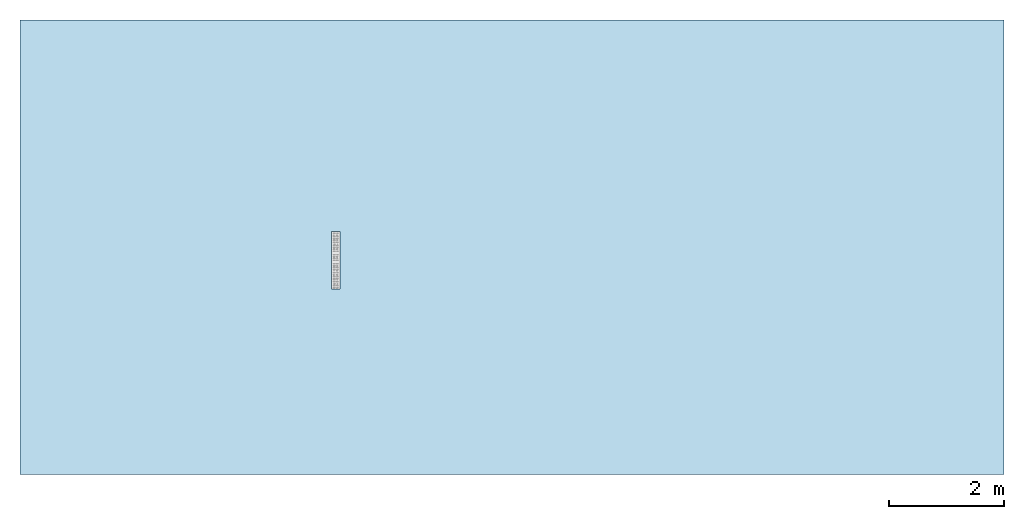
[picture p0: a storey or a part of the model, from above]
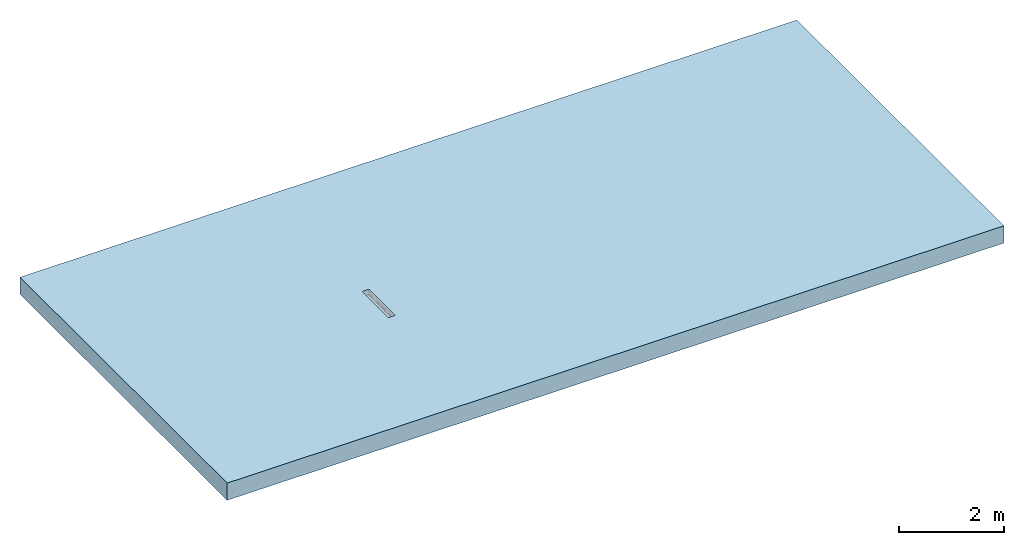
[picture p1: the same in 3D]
Properties of the parts of a building model (IFC2X3)

# File
Description: ViewDefinition [CoordinationView]
File name: 7955 - Centre Stone - 1000mm LG.ifc
Time: 2013-08-30T17:40:42
Written by: Autodesk Revit 2013
Made in: 20120221_2030(x64)

# IfcProject, Project Number
LongName: Project Name; Phase: Project Status

# IfcSite, Default
RefLatitude: 42, 21, 30, 344238; RefLongitude: -71, -3, -35, -194702; RefElevation: 0 mm

# IfcBuilding
Pset_BuildingCommon - NumberOfStoreys: 1
Other - Client Name: Owner; Project Number: Project Number; Project Name: Project Name; Project Issue Date: Issue Date; Project Status: Project Status; Project Address: ## Street City, State Zip

# IfcBuildingStorey, Level 1
LongName: Level 1; Elevation: 0 mm
Constraints - Elevation Base: 0; Elevation: 0 mm
Graphics - Line Weight: 1; Line Pattern: Center; Symbol at End 2 Default: yes; Symbol at End 1 Default: no; Symbol: M_Level Head - Circle: M_Level Head - Circle; Color: 0
Identity Data - Name: Level 1; Building Story: yes; Structural: no
Dimensions - Computation Height: 0 mm

# IfcBuildingElementProxy: 7955 - Centre Stone - 1000mm LG, Civil-Drainage-Channel-ACO-KerbDrain-HB255:7955 - Centre Stone - 1000mm LG:7955 - Centre Stone - 1000mm LG:754467
In: Level 1
Material: ACO Polymer Concrete.
Constraints - Moves With Nearby Elements: no; Level: Level: Level 1
Phasing - Phase Created: New Construction
Dimensions - Volume: 13058990 mm3; Access Depth: 2000 mm; Void Width: 150 mm; Void Start: 0 mm; RH Void Start: -2000 mm; RH Hole End: -2005 mm; LH Void End: -2005 mm; Void Depth: -125 mm; Void Length: 1000 mm; LH Void Start: -2000 mm
Pset_BuildingElementProxyCommon - Reference: 7955 - Centre Stone - 1000mm LG
Identity Data - Installation guidelines: http://www.aco.co.uk/download.php?id=120; OmniClass Number: 23.70.50.24; Manufacturer: ACO Technologies plc - ACO Water Management Division; Product Page URL: http://www.aco.co.uk/product_detail.php?id=3; Model: ACO KerbDrain HB255; Maintenance guidelines: http://www.aco.co.uk/download.php?id=120; Telephone: +44 (0)1462 816666; Fax: +44 (0)1462 815895; OmniClass Title: Rainwater Removal; Cost: 0; Assembly Code: D2040; Product Code: 7955; Address: ACO Business Park, Hitchin Road, Shefford, Bedfordshire, United Kingdom SG17 5TE; Model Description: Combined kerb and drainage system; e-mail Technical: technical@aco.co.uk; Product brochure: http://www.aco.co.uk/download.php?id=120; Price: POA - contact ACO; URL: www.aco.co.uk; Assembly Description: Rain Water Drainage; Type Comments: ACO KerbDrain HB255 half battered centre stone 1000mm long ACO KerbDrain HB255 half battered centre stone 1000mm long; e-mail Sales: customersupport@aco.co.uk
Green Building Properties - Channel Recyclable: Fully recyclable; Channel Recycled Material Content: 20% minimum; End Cap Recycled Material Content: N/A; End Cap Recyclable: N/A; Access Cover/Frame Recyclable: N/A; Access Cover/Frame Recycled Material Content: N/A
General - TagNumber: 0.000000; SerialNumber: 0.000000
Data - Product Dimensions: 1000mm x 150mm x 125mm (LxWxH); ACO Hydraulic Design Software: http://www.acodesign.co.uk; Product Standard: BS EN 1433:2002, CE marked, Kitemarked; Drainage Slot Width: 8mm; Connection Pipe O.D: N/A; Drainage Slot Intake area: 18397mm²/m; Concrete Surround Volume - Load Class A 15 - D 400 - Grass or Asphalt Pavement: N/A; Concrete Surround Volume - Load Class A 15 - D 400 - Concrete Pavement: N/A; Invert Depth: 105mm; Load Class: A 15 - D 400; Hydraulic Performance: http://www.aco.co.uk/download.php?id=120; Product Weight: 24.7 Kg; Channel C.S.A: 0.005m²; Installation - Concrete Grade: Refer to brochure
Materials and Finishes - Access Cover/Frame Finish: N/A; Access Cover/Frame Material: N/A; End Cap Colour: N/A; End Cap Material: N/A; Channel Colour: Grey; Access Cover/Frame Colour: N/A; Channel Material: Vienite® Synthetic Resin Concrete
Construction - LH drop kerb: no; HB255 - 500: no; RH drop kerb: no; Centre Stone: yes; Access Unit: no; HB255 - 1000: no; Closing end cap: no
Other - CreatedBy: www.aco.co.uk; Revision: 1

# IfcOpeningElement: Recess (3)
In: Level 1
Structural - Structural: no; Enable Analytical Model: no
Dimensions - Thickness: 400 mm; Volume: 54017250000 mm3; Perimeter: 50000 mm; Area: 135090000 mm2
Phasing - Phase Created: New Construction
Constraints - Related to Mass: no; Height Offset From Level: 0 mm; Level: Level: Level 1; Room Bounding: yes
Construction - Default Thickness: 400 mm; Function: 0
Graphics - Coarse Scale Fill Color: 0
Analytical Properties - Absorptance: 0.1; Roughness: 1
Materials and Finishes - Structural Material: Plant

# IfcSlab: Floor:Generic Floor - 400mm, Floor:Generic Floor - 400mm:193825
In: Level 1
PredefinedType: FLOOR; Material: Plant 400 mm
Structural - Structural: no; Enable Analytical Model: no
Dimensions - Thickness: 400 mm; Volume: 54017250000 mm3; Perimeter: 50000 mm; Area: 135090000 mm2
Phasing - Phase Created: New Construction
Constraints - Related to Mass: no; Height Offset From Level: 0 mm; Level: Level: Level 1; Room Bounding: yes
Pset_SlabCommon - Reference: Generic Floor - 400mm; IsExternal: no; LoadBearing: yes
Construction - Default Thickness: 400 mm; Function: 0
Graphics - Coarse Scale Fill Color: 0
Analytical Properties - Absorptance: 0.1; Roughness: 1
Materials and Finishes - Structural Material: Plant
